One B-rep face of a CAD part: STEP entity #264.
In plain terms, the planar face has unit normal (1, 0, 0).
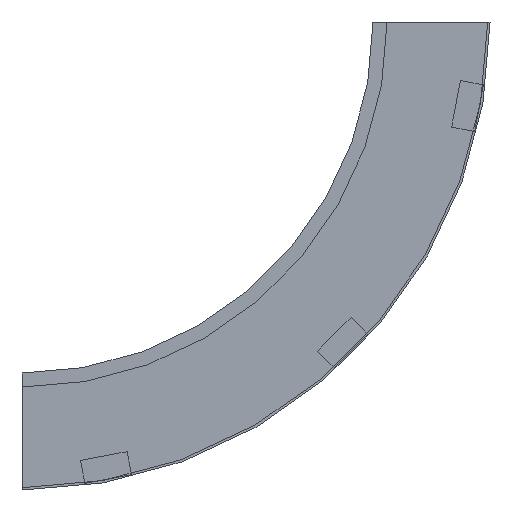
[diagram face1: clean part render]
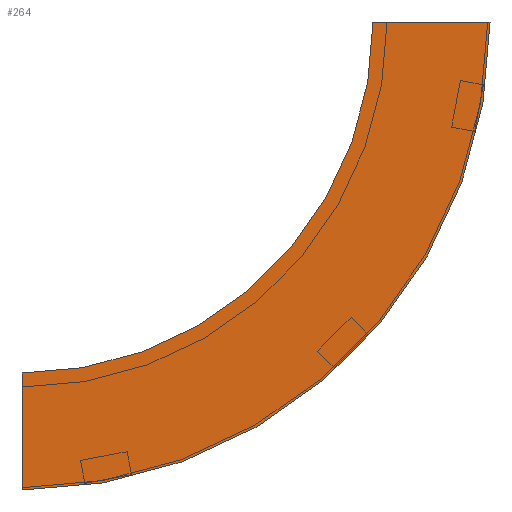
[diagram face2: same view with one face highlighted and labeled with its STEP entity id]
Its self-contained STEP definition (entity closure, numbers rounded to 3 decimals):
#21 = DIRECTION ( 'NONE',  ( 0., 1., 0. ) ) ;
#28 = LINE ( 'NONE', #521, #276 ) ;
#41 = FACE_OUTER_BOUND ( 'NONE', #49, .T. ) ;
#43 = EDGE_CURVE ( 'NONE', #368, #490, #332, .T. ) ;
#49 = EDGE_LOOP ( 'NONE', ( #281, #499, #506, #338 ) ) ;
#69 = DIRECTION ( 'NONE',  ( 0., -1., 0. ) ) ;
#70 = CARTESIAN_POINT ( 'NONE',  ( 0., 300., 0. ) ) ;
#72 = CIRCLE ( 'NONE', #447, 300. ) ;
#166 = VECTOR ( 'NONE', #21, 1000. ) ;
#171 = EDGE_CURVE ( 'NONE', #179, #198, #28, .T. ) ;
#177 = DIRECTION ( 'NONE',  ( 0., 0., 1. ) ) ;
#179 = VERTEX_POINT ( 'NONE', #529 ) ;
#183 = PLANE ( 'NONE',  #351 ) ;
#198 = VERTEX_POINT ( 'NONE', #377 ) ;
#213 = DIRECTION ( 'NONE',  ( 0., 0., 1. ) ) ;
#224 = EDGE_CURVE ( 'NONE', #368, #179, #484, .T. ) ;
#233 = CARTESIAN_POINT ( 'NONE',  ( 0., -100., 0. ) ) ;
#251 = CARTESIAN_POINT ( 'NONE',  ( 0., 0., 0. ) ) ;
#264 = ADVANCED_FACE ( 'NONE', ( #41 ), #183, .F. ) ;
#266 = AXIS2_PLACEMENT_3D ( 'NONE', #70, #302, #574 ) ;
#276 = VECTOR ( 'NONE', #213, 1000. ) ;
#281 = ORIENTED_EDGE ( 'NONE', *, *, #552, .F. ) ;
#299 = DIRECTION ( 'NONE',  ( 1., 0., 0. ) ) ;
#302 = DIRECTION ( 'NONE',  ( 1., 0., 0. ) ) ;
#332 = LINE ( 'NONE', #505, #166 ) ;
#338 = ORIENTED_EDGE ( 'NONE', *, *, #171, .T. ) ;
#351 = AXIS2_PLACEMENT_3D ( 'NONE', #233, #397, #177 ) ;
#368 = VERTEX_POINT ( 'NONE', #577 ) ;
#377 = CARTESIAN_POINT ( 'NONE',  ( 0., 300., -300. ) ) ;
#397 = DIRECTION ( 'NONE',  ( -1., 0., 0. ) ) ;
#447 = AXIS2_PLACEMENT_3D ( 'NONE', #471, #299, #69 ) ;
#471 = CARTESIAN_POINT ( 'NONE',  ( 0., 300., 0. ) ) ;
#484 = CIRCLE ( 'NONE', #266, 400. ) ;
#490 = VERTEX_POINT ( 'NONE', #251 ) ;
#499 = ORIENTED_EDGE ( 'NONE', *, *, #43, .F. ) ;
#505 = CARTESIAN_POINT ( 'NONE',  ( 0., -100., 0. ) ) ;
#506 = ORIENTED_EDGE ( 'NONE', *, *, #224, .T. ) ;
#521 = CARTESIAN_POINT ( 'NONE',  ( 0., 300., -400. ) ) ;
#529 = CARTESIAN_POINT ( 'NONE',  ( 0., 300., -400. ) ) ;
#552 = EDGE_CURVE ( 'NONE', #490, #198, #72, .T. ) ;
#574 = DIRECTION ( 'NONE',  ( 0., -1., 0. ) ) ;
#577 = CARTESIAN_POINT ( 'NONE',  ( 0., -100., 0. ) ) ;
